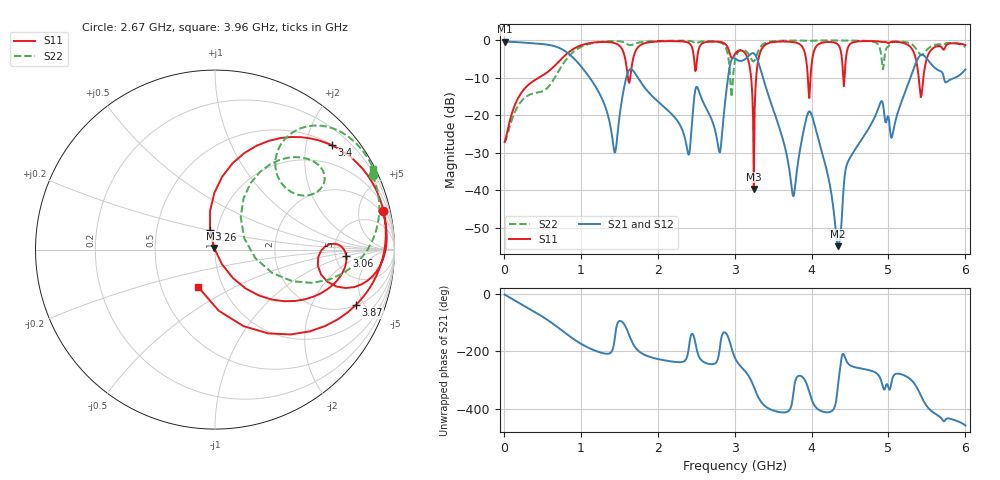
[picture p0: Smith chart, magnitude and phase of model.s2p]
! G_pp200: plane-cavity model as kisi uses it (kisi_pi::cavity_modal), 1 ohm ports
# Hz S RI R 1
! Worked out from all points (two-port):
!   600 points, 10 MHz to 6 GHz, reference 1 ohm
!   highest |S21| = -0.38 dB at 10 MHz (marker M1); lowest = -54.9 dB at 4.34 GHz (marker M2)
!   |S21| within 3 dB of the highest: start of sweep to 829.7 MHz
!   lowest |S11| = -39.7 dB at 3.25 GHz (marker M3), VSWR 1.02, Z = 0.99 + j0.0181 ohm
!   |S11| at or under -10 dB: start of sweep to 452.9 MHz; 3.214 GHz to 3.28 GHz (65.6 MHz wide, 2.02 % of centre); 5.393 GHz to 5.454 GHz (60.57 MHz wide, 1.12 % of centre) (the widest 3 of 6)
!   |S22| runs from -27.2 to 0.0 dB; largest |S21 - S12| = 0
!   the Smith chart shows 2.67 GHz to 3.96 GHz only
!   S11 on the Smith chart (normalised r, x): 2.67 GHz: 1.67, +8.56; 3.06 GHz: 6.31, -1.01; 3.26 GHz: 0.92, +0.21; 3.4 GHz: 0.52, +2.52; 3.87 GHz: 2.04, -4.37; 3.96 GHz: 0.76, -0.33
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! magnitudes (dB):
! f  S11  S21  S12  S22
! 10 MHz  -27.1  -0.4  -0.4  -27.2
! 1.01 GHz  -1.3  -7.1  -7.1  -1.7
! 1.44 GHz  -0.8  -30.0  -30.0  -0.2
! 1.64 GHz  -10.4  -7.7  -7.7  -1.3
! 2.01 GHz  -0.3  -16.5  -16.5  -0.2
! 2.39 GHz  -0.6  -29.7  -29.7  -0.1
! 2.67 GHz  -0.4  -19.7  -19.7  -0.3
! 2.81 GHz  -0.4  -29.9  -29.9  -0.6
! 3.01 GHz  -3.5  -4.9  -4.9  -5.0
! 3.06 GHz  -2.7  -5.5  -5.5  -2.9
! 3.25 GHz  -39.7  -3.5  -3.5  -5.6
! 3.26 GHz  -18.8  -3.7  -3.7  -5.4
! 3.4 GHz  -1.2  -12.1  -12.1  -0.7
! 3.76 GHz  -0.5  -41.6  -41.6  -0.1
! 3.87 GHz  -1.5  -26.9  -26.9  -0.1
! 3.96 GHz  -12.9  -19.2  -19.2  -0.1
! 4.01 GHz  -5.0  -20.4  -20.4  -0.1
! 4.34 GHz  -1.1  -54.9  -54.9  0.0
! 4.48 GHz  -1.6  -32.1  -32.1  -0.1
! 5.01 GHz  -0.7  -21.8  -21.8  -1.4
! 5.41 GHz  -13.6  -4.1  -4.1  -3.7
! 6 GHz  -1.3  -7.8  -7.8  -1.8
